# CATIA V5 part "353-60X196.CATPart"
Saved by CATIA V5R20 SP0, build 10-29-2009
Part number: 353-60x196
Definition: NONE
Nomenclature: 353-60x196
Source: Unknown
Description: 353-60x196
Bounding box of the stored display mesh (mm): x -12 to 184, y -42 to 42, z -42 to 42
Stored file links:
  C:\Users\Utente\Desktop\IO LAVORO\3D X SITO CF\X SITO\PLASTICA\353\353-60X196.CATPart

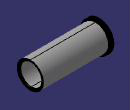
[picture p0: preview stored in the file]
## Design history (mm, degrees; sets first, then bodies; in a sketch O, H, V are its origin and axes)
Body1 "353-60x196" (main body)
  Solid1: solid without history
